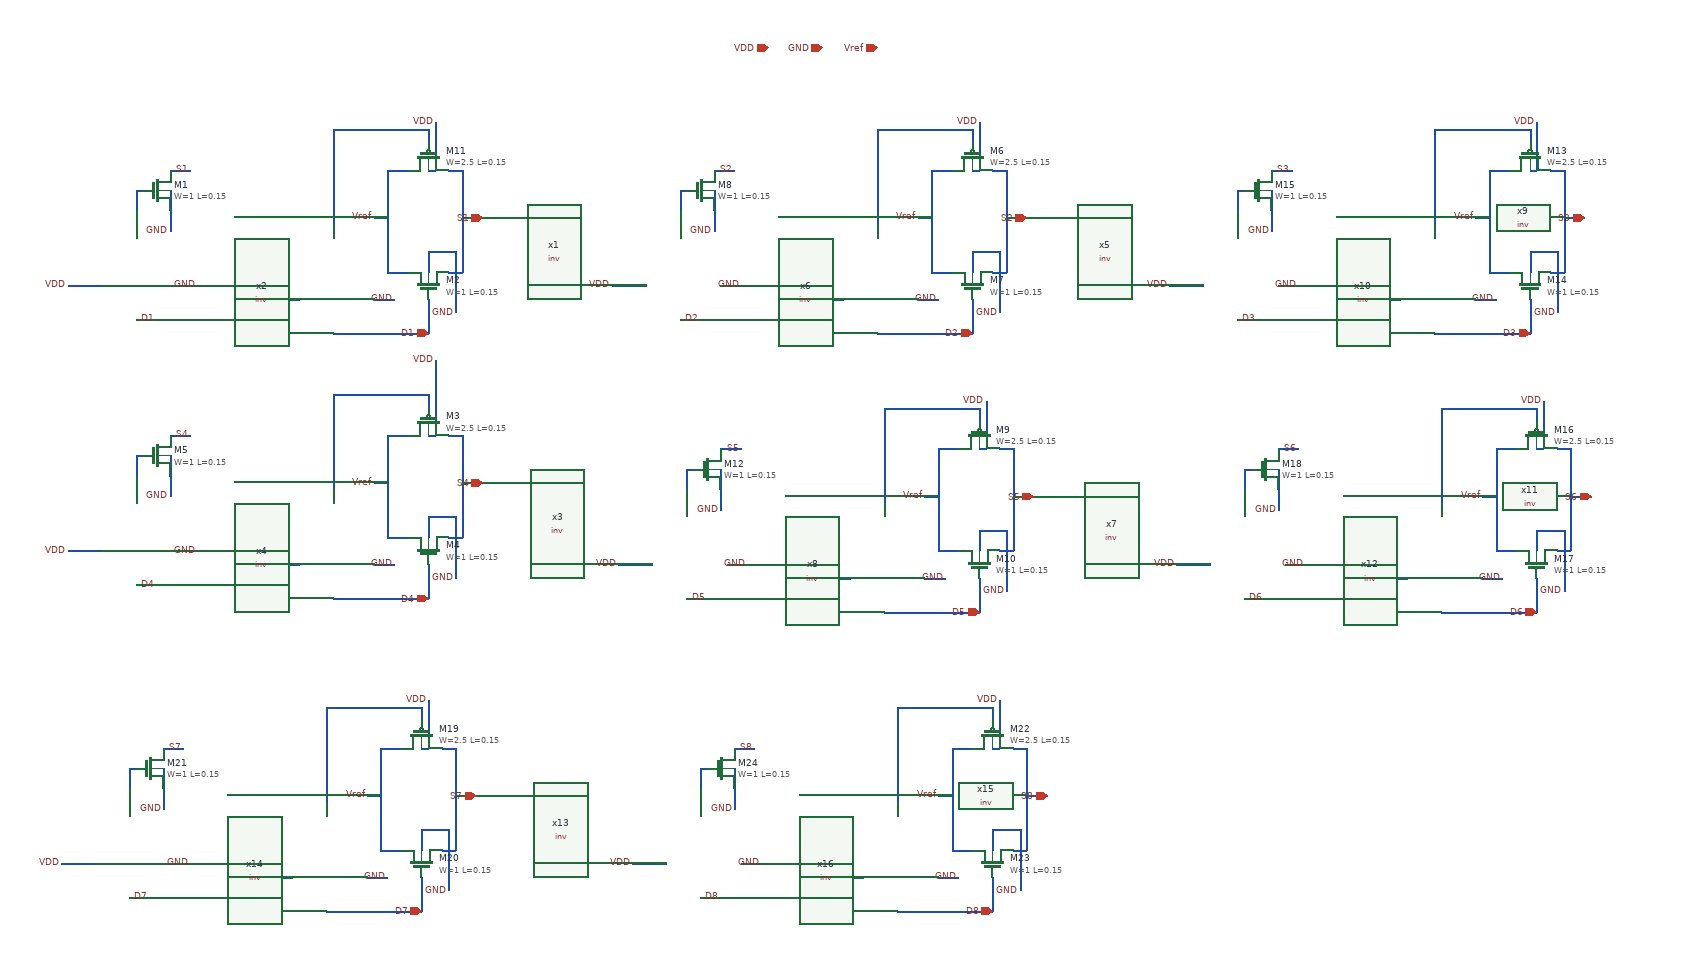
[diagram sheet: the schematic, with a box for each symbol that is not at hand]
v {xschem version=3.4.8RC file_version=1.2}
G {}
K {}
V {}
S {}
E {}
N -90 80 -60 80 {lab=Vref}
N -90 80 -90 230 {lab=Vref}
N -90 230 -60 230 {lab=Vref}
N 0 80 20 80 {lab=S1}
N 20 80 20 230 {lab=S1}
N 0 230 20 230 {lab=S1}
N -30 270 -30 310 {lab=D1}
N -30 200 -30 230 {lab=GND}
N -30 200 10 200 {lab=GND}
N 10 200 10 290 {lab=GND}
N -30 80 -20 80 {lab=VDD}
N -20 10 -20 80 {lab=VDD}
N -170 20 -30 20 {lab=#net1}
N -30 20 -30 40 {lab=#net1}
N -170 320 -50 320 {lab=D1}
N -270 270 -220 270 {lab=VDD}
N -170 20 -170 160 {lab=#net1}
N -110 270 -80 270 {lab=GND}
N -560 250 -510 250 {lab=VDD}
N -400 250 -370 250 {lab=GND}
N -460 110 -460 140 {lab=#net2}
N -460 110 -450 110 {lab=#net2}
N -410 110 -410 140 {lab=GND}
N -460 300 -430 300 {lab=D1}
N -410 80 -380 80 {lab=S1}
N -410 140 -410 170 {lab=GND}
N -30 310 -30 320 {lab=D1}
N -50 320 -30 320 {lab=D1}
N -110 150 -90 150 {lab=Vref}
N 20 150 50 150 {lab=S1}
N -90 470 -60 470 {lab=Vref}
N -90 470 -90 620 {lab=Vref}
N -90 620 -60 620 {lab=Vref}
N 0 470 20 470 {lab=S4}
N 20 470 20 620 {lab=S4}
N 0 620 20 620 {lab=S4}
N -30 660 -30 700 {lab=D4}
N -30 590 -30 620 {lab=GND}
N -30 590 10 590 {lab=GND}
N 10 590 10 680 {lab=GND}
N -170 410 -30 410 {lab=#net3}
N -30 410 -30 430 {lab=#net3}
N -170 710 -50 710 {lab=D4}
N -270 660 -220 660 {lab=VDD}
N -170 410 -170 550 {lab=#net3}
N -110 660 -80 660 {lab=GND}
N -560 640 -510 640 {lab=VDD}
N -400 640 -370 640 {lab=GND}
N -460 500 -460 530 {lab=#net4}
N -460 500 -450 500 {lab=#net4}
N -410 500 -410 530 {lab=GND}
N -460 690 -430 690 {lab=D4}
N -410 470 -380 470 {lab=S4}
N -410 530 -410 560 {lab=GND}
N -30 700 -30 710 {lab=D4}
N -50 710 -30 710 {lab=D4}
N -110 540 -90 540 {lab=Vref}
N 20 540 50 540 {lab=S4}
N 710 80 740 80 {lab=Vref}
N 710 80 710 230 {lab=Vref}
N 710 230 740 230 {lab=Vref}
N 800 80 820 80 {lab=S2}
N 820 80 820 230 {lab=S2}
N 800 230 820 230 {lab=S2}
N 770 270 770 310 {lab=D2}
N 770 200 770 230 {lab=GND}
N 770 200 810 200 {lab=GND}
N 810 200 810 290 {lab=GND}
N 770 80 780 80 {lab=VDD}
N 780 10 780 80 {lab=VDD}
N 630 20 770 20 {lab=#net5}
N 770 20 770 40 {lab=#net5}
N 630 320 750 320 {lab=D2}
N 530 270 580 270 {lab=VDD}
N 630 20 630 160 {lab=#net5}
N 690 270 720 270 {lab=GND}
N 240 250 290 250 {lab=VDD}
N 400 250 430 250 {lab=GND}
N 340 110 340 140 {lab=#net6}
N 340 110 350 110 {lab=#net6}
N 390 110 390 140 {lab=GND}
N 340 300 370 300 {lab=D2}
N 390 80 420 80 {lab=S2}
N 390 140 390 170 {lab=GND}
N 770 310 770 320 {lab=D2}
N 750 320 770 320 {lab=D2}
N 690 150 710 150 {lab=Vref}
N 820 150 850 150 {lab=S2}
N 720 490 750 490 {lab=Vref}
N 720 490 720 640 {lab=Vref}
N 720 640 750 640 {lab=Vref}
N 810 490 830 490 {lab=S5}
N 830 490 830 640 {lab=S5}
N 810 640 830 640 {lab=S5}
N 780 680 780 720 {lab=D5}
N 780 610 780 640 {lab=GND}
N 780 610 820 610 {lab=GND}
N 820 610 820 700 {lab=GND}
N 780 490 790 490 {lab=VDD}
N 790 420 790 490 {lab=VDD}
N 640 430 780 430 {lab=#net7}
N 780 430 780 450 {lab=#net7}
N 640 730 760 730 {lab=D5}
N 540 680 590 680 {lab=VDD}
N 640 430 640 570 {lab=#net7}
N 700 680 730 680 {lab=GND}
N 250 660 300 660 {lab=VDD}
N 410 660 440 660 {lab=GND}
N 350 520 350 550 {lab=#net8}
N 350 520 360 520 {lab=#net8}
N 400 520 400 550 {lab=GND}
N 350 710 380 710 {lab=D5}
N 400 490 430 490 {lab=S5}
N 400 550 400 580 {lab=GND}
N 780 720 780 730 {lab=D5}
N 760 730 780 730 {lab=D5}
N 700 560 720 560 {lab=Vref}
N 830 560 860 560 {lab=S5}
N 1530 80 1560 80 {lab=Vref}
N 1530 80 1530 230 {lab=Vref}
N 1530 230 1560 230 {lab=Vref}
N 1620 80 1640 80 {lab=S3}
N 1640 80 1640 230 {lab=S3}
N 1620 230 1640 230 {lab=S3}
N 1590 270 1590 310 {lab=D3}
N 1590 200 1590 230 {lab=GND}
N 1590 200 1630 200 {lab=GND}
N 1630 200 1630 290 {lab=GND}
N 1590 80 1600 80 {lab=VDD}
N 1600 10 1600 80 {lab=VDD}
N 1450 20 1590 20 {lab=#net9}
N 1590 20 1590 40 {lab=#net9}
N 1450 320 1570 320 {lab=D3}
N 1350 270 1400 270 {lab=VDD}
N 1450 20 1450 160 {lab=#net9}
N 1510 270 1540 270 {lab=GND}
N 1060 250 1110 250 {lab=VDD}
N 1220 250 1250 250 {lab=GND}
N 1160 110 1160 140 {lab=#net10}
N 1160 110 1170 110 {lab=#net10}
N 1210 110 1210 140 {lab=GND}
N 1160 300 1190 300 {lab=D3}
N 1210 80 1240 80 {lab=S3}
N 1210 140 1210 170 {lab=GND}
N 1590 310 1590 320 {lab=D3}
N 1570 320 1590 320 {lab=D3}
N 1510 150 1530 150 {lab=Vref}
N 1640 150 1670 150 {lab=S3}
N 1540 490 1570 490 {lab=Vref}
N 1540 490 1540 640 {lab=Vref}
N 1540 640 1570 640 {lab=Vref}
N 1630 490 1650 490 {lab=S6}
N 1650 490 1650 640 {lab=S6}
N 1630 640 1650 640 {lab=S6}
N 1600 680 1600 720 {lab=D6}
N 1600 610 1600 640 {lab=GND}
N 1600 610 1640 610 {lab=GND}
N 1640 610 1640 700 {lab=GND}
N 1600 490 1610 490 {lab=VDD}
N 1610 420 1610 490 {lab=VDD}
N 1460 430 1600 430 {lab=#net11}
N 1600 430 1600 450 {lab=#net11}
N 1460 730 1580 730 {lab=D6}
N 1360 680 1410 680 {lab=VDD}
N 1460 430 1460 570 {lab=#net11}
N 1520 680 1550 680 {lab=GND}
N 1070 660 1120 660 {lab=VDD}
N 1230 660 1260 660 {lab=GND}
N 1170 520 1170 550 {lab=#net12}
N 1170 520 1180 520 {lab=#net12}
N 1220 520 1220 550 {lab=GND}
N 1170 710 1200 710 {lab=D6}
N 1220 490 1250 490 {lab=S6}
N 1220 550 1220 580 {lab=GND}
N 1600 720 1600 730 {lab=D6}
N 1580 730 1600 730 {lab=D6}
N 1520 560 1540 560 {lab=Vref}
N 1650 560 1680 560 {lab=S6}
N -100 930 -70 930 {lab=Vref}
N -100 930 -100 1080 {lab=Vref}
N -100 1080 -70 1080 {lab=Vref}
N -10 930 10 930 {lab=S7}
N 10 930 10 1080 {lab=S7}
N -10 1080 10 1080 {lab=S7}
N -40 1120 -40 1160 {lab=D7}
N -40 1050 -40 1080 {lab=GND}
N -40 1050 0 1050 {lab=GND}
N 0 1050 0 1140 {lab=GND}
N -40 930 -30 930 {lab=VDD}
N -30 860 -30 930 {lab=VDD}
N -180 870 -40 870 {lab=#net13}
N -40 870 -40 890 {lab=#net13}
N -180 1170 -60 1170 {lab=D7}
N -280 1120 -230 1120 {lab=VDD}
N -180 870 -180 1010 {lab=#net13}
N -120 1120 -90 1120 {lab=GND}
N -570 1100 -520 1100 {lab=VDD}
N -410 1100 -380 1100 {lab=GND}
N -470 960 -470 990 {lab=#net14}
N -470 960 -460 960 {lab=#net14}
N -420 960 -420 990 {lab=GND}
N -470 1150 -440 1150 {lab=D7}
N -420 930 -390 930 {lab=S7}
N -420 990 -420 1020 {lab=GND}
N -40 1160 -40 1170 {lab=D7}
N -60 1170 -40 1170 {lab=D7}
N -120 1000 -100 1000 {lab=Vref}
N 10 1000 40 1000 {lab=S7}
N 740 930 770 930 {lab=Vref}
N 740 930 740 1080 {lab=Vref}
N 740 1080 770 1080 {lab=Vref}
N 830 930 850 930 {lab=S8}
N 850 930 850 1080 {lab=S8}
N 830 1080 850 1080 {lab=S8}
N 800 1120 800 1160 {lab=D8}
N 800 1050 800 1080 {lab=GND}
N 800 1050 840 1050 {lab=GND}
N 840 1050 840 1140 {lab=GND}
N 800 930 810 930 {lab=VDD}
N 810 860 810 930 {lab=VDD}
N 660 870 800 870 {lab=#net15}
N 800 870 800 890 {lab=#net15}
N 660 1170 780 1170 {lab=D8}
N 560 1120 610 1120 {lab=VDD}
N 660 870 660 1010 {lab=#net15}
N 720 1120 750 1120 {lab=GND}
N 270 1100 320 1100 {lab=VDD}
N 430 1100 460 1100 {lab=GND}
N 370 960 370 990 {lab=#net16}
N 370 960 380 960 {lab=#net16}
N 420 960 420 990 {lab=GND}
N 370 1150 400 1150 {lab=D8}
N 420 930 450 930 {lab=S8}
N 420 990 420 1020 {lab=GND}
N 800 1160 800 1170 {lab=D8}
N 780 1170 800 1170 {lab=D8}
N 720 1000 740 1000 {lab=Vref}
N 850 1000 880 1000 {lab=S8}
N -30 470 -20 470 {lab=VDD}
N -20 360 -20 470 {lab=VDD}
C {iopin.sym} 470 -100 0 0 {name=p4 lab=VDD}
C {iopin.sym} 550 -100 0 0 {name=p5 lab=GND}
C {sky130_fd_pr/pfet_01v8.sym} -30 60 3 1 {name=M11
L=0.15
W=2.5
nf=1 mult=1
model=pfet_01v8
spiceprefix=X
}
C {sky130_fd_pr/nfet_01v8.sym} -30 250 1 1 {name=M2
L=0.15
W=1  
nf=1 mult=1
model=nfet_01v8
spiceprefix=X
}
C {sky130_fd_pr/nfet_01v8.sym} -430 110 0 0 {name=M1
L=0.15
W=1  
nf=1 mult=1
model=nfet_01v8
spiceprefix=X
}
C {inv.sym} 60 250 3 0 {name=x1}
C {lab_wire.sym} -270 270 0 0 {name=p6 sig_type=std_logic lab=VDD}
C {lab_wire.sym} -80 270 0 0 {name=p7 sig_type=std_logic lab=GND}
C {inv.sym} -230 230 3 0 {name=x2}
C {lab_wire.sym} -560 250 0 0 {name=p8 sig_type=std_logic lab=VDD}
C {lab_wire.sym} -370 250 0 0 {name=p9 sig_type=std_logic lab=GND}
C {lab_wire.sym} -430 300 0 0 {name=p10 sig_type=std_logic lab=D1}
C {lab_wire.sym} -380 80 0 0 {name=p11 sig_type=std_logic lab=S1}
C {lab_wire.sym} -20 10 0 0 {name=p12 sig_type=std_logic lab=VDD}
C {lab_wire.sym} 10 290 0 0 {name=p13 sig_type=std_logic lab=GND}
C {lab_wire.sym} -410 170 0 0 {name=p14 sig_type=std_logic lab=GND}
C {iopin.sym} -30 320 0 0 {name=p1 lab=D1}
C {iopin.sym} 630 -100 0 0 {name=p2 lab=Vref}
C {lab_wire.sym} -110 150 0 0 {name=p3 sig_type=std_logic lab=Vref}
C {iopin.sym} 50 150 0 0 {name=p15 lab=S1
}
C {sky130_fd_pr/pfet_01v8.sym} -30 450 3 1 {name=M3
L=0.15
W=2.5
nf=1 mult=1
model=pfet_01v8
spiceprefix=X
}
C {sky130_fd_pr/nfet_01v8.sym} -30 640 1 1 {name=M4
L=0.15
W=1  
nf=1 mult=1
model=nfet_01v8
spiceprefix=X
}
C {sky130_fd_pr/nfet_01v8.sym} -430 500 0 0 {name=M5
L=0.15
W=1  
nf=1 mult=1
model=nfet_01v8
spiceprefix=X
}
C {inv.sym} 60 640 3 0 {name=x3}
C {lab_wire.sym} -270 660 0 0 {name=p16 sig_type=std_logic lab=VDD}
C {lab_wire.sym} -80 660 0 0 {name=p17 sig_type=std_logic lab=GND}
C {inv.sym} -230 620 3 0 {name=x4}
C {lab_wire.sym} -560 640 0 0 {name=p18 sig_type=std_logic lab=VDD}
C {lab_wire.sym} -370 640 0 0 {name=p19 sig_type=std_logic lab=GND}
C {lab_wire.sym} -430 690 0 0 {name=p20 sig_type=std_logic lab=D4}
C {lab_wire.sym} -380 470 0 0 {name=p21 sig_type=std_logic lab=S4}
C {lab_wire.sym} 10 680 0 0 {name=p22 sig_type=std_logic lab=GND}
C {lab_wire.sym} -410 560 0 0 {name=p23 sig_type=std_logic lab=GND}
C {iopin.sym} -30 710 0 0 {name=p24 lab=D4}
C {lab_wire.sym} -110 540 0 0 {name=p25 sig_type=std_logic lab=Vref}
C {iopin.sym} 50 540 0 0 {name=p26 lab=S4
}
C {sky130_fd_pr/pfet_01v8.sym} 770 60 3 1 {name=M6
L=0.15
W=2.5
nf=1 mult=1
model=pfet_01v8
spiceprefix=X
}
C {sky130_fd_pr/nfet_01v8.sym} 770 250 1 1 {name=M7
L=0.15
W=1  
nf=1 mult=1
model=nfet_01v8
spiceprefix=X
}
C {sky130_fd_pr/nfet_01v8.sym} 370 110 0 0 {name=M8
L=0.15
W=1  
nf=1 mult=1
model=nfet_01v8
spiceprefix=X
}
C {inv.sym} 860 250 3 0 {name=x5}
C {lab_wire.sym} 530 270 0 0 {name=p27 sig_type=std_logic lab=VDD}
C {lab_wire.sym} 720 270 0 0 {name=p28 sig_type=std_logic lab=GND}
C {inv.sym} 570 230 3 0 {name=x6}
C {lab_wire.sym} 240 250 0 0 {name=p29 sig_type=std_logic lab=VDD}
C {lab_wire.sym} 430 250 0 0 {name=p30 sig_type=std_logic lab=GND}
C {lab_wire.sym} 370 300 0 0 {name=p31 sig_type=std_logic lab=D2}
C {lab_wire.sym} 420 80 0 0 {name=p32 sig_type=std_logic lab=S2}
C {lab_wire.sym} 780 10 0 0 {name=p33 sig_type=std_logic lab=VDD}
C {lab_wire.sym} 810 290 0 0 {name=p34 sig_type=std_logic lab=GND}
C {lab_wire.sym} 390 170 0 0 {name=p35 sig_type=std_logic lab=GND}
C {iopin.sym} 770 320 0 0 {name=p36 lab=D2}
C {lab_wire.sym} 690 150 0 0 {name=p37 sig_type=std_logic lab=Vref}
C {iopin.sym} 850 150 0 0 {name=p38 lab=S2
}
C {sky130_fd_pr/pfet_01v8.sym} 780 470 3 1 {name=M9
L=0.15
W=2.5
nf=1 mult=1
model=pfet_01v8
spiceprefix=X
}
C {sky130_fd_pr/nfet_01v8.sym} 780 660 1 1 {name=M10
L=0.15
W=1  
nf=1 mult=1
model=nfet_01v8
spiceprefix=X
}
C {sky130_fd_pr/nfet_01v8.sym} 380 520 0 0 {name=M12
L=0.15
W=1  
nf=1 mult=1
model=nfet_01v8
spiceprefix=X
}
C {inv.sym} 870 660 3 0 {name=x7}
C {lab_wire.sym} 540 680 0 0 {name=p39 sig_type=std_logic lab=VDD}
C {lab_wire.sym} 730 680 0 0 {name=p40 sig_type=std_logic lab=GND}
C {inv.sym} 580 640 3 0 {name=x8}
C {lab_wire.sym} 250 660 0 0 {name=p41 sig_type=std_logic lab=VDD}
C {lab_wire.sym} 440 660 0 0 {name=p42 sig_type=std_logic lab=GND}
C {lab_wire.sym} 380 710 0 0 {name=p43 sig_type=std_logic lab=D5}
C {lab_wire.sym} 430 490 0 0 {name=p44 sig_type=std_logic lab=S5}
C {lab_wire.sym} 790 420 0 0 {name=p45 sig_type=std_logic lab=VDD}
C {lab_wire.sym} 820 700 0 0 {name=p46 sig_type=std_logic lab=GND}
C {lab_wire.sym} 400 580 0 0 {name=p47 sig_type=std_logic lab=GND}
C {iopin.sym} 780 730 0 0 {name=p48 lab=D5}
C {lab_wire.sym} 700 560 0 0 {name=p49 sig_type=std_logic lab=Vref}
C {iopin.sym} 860 560 0 0 {name=p50 lab=S5
}
C {sky130_fd_pr/pfet_01v8.sym} 1590 60 3 1 {name=M13
L=0.15
W=2.5
nf=1 mult=1
model=pfet_01v8
spiceprefix=X
}
C {sky130_fd_pr/nfet_01v8.sym} 1590 250 1 1 {name=M14
L=0.15
W=1  
nf=1 mult=1
model=nfet_01v8
spiceprefix=X
}
C {sky130_fd_pr/nfet_01v8.sym} 1190 110 0 0 {name=M15
L=0.15
W=1  
nf=1 mult=1
model=nfet_01v8
spiceprefix=X
}
C {inv.sym} 1680 250 3 0 {name=x9}
C {lab_wire.sym} 1350 270 0 0 {name=p51 sig_type=std_logic lab=VDD}
C {lab_wire.sym} 1540 270 0 0 {name=p52 sig_type=std_logic lab=GND}
C {inv.sym} 1390 230 3 0 {name=x10}
C {lab_wire.sym} 1060 250 0 0 {name=p53 sig_type=std_logic lab=VDD}
C {lab_wire.sym} 1250 250 0 0 {name=p54 sig_type=std_logic lab=GND}
C {lab_wire.sym} 1190 300 0 0 {name=p55 sig_type=std_logic lab=D3}
C {lab_wire.sym} 1240 80 0 0 {name=p56 sig_type=std_logic lab=S3}
C {lab_wire.sym} 1600 10 0 0 {name=p57 sig_type=std_logic lab=VDD}
C {lab_wire.sym} 1630 290 0 0 {name=p58 sig_type=std_logic lab=GND}
C {lab_wire.sym} 1210 170 0 0 {name=p59 sig_type=std_logic lab=GND}
C {iopin.sym} 1590 320 0 0 {name=p60 lab=D3}
C {lab_wire.sym} 1510 150 0 0 {name=p61 sig_type=std_logic lab=Vref}
C {iopin.sym} 1670 150 0 0 {name=p62 lab=S3
}
C {sky130_fd_pr/pfet_01v8.sym} 1600 470 3 1 {name=M16
L=0.15
W=2.5
nf=1 mult=1
model=pfet_01v8
spiceprefix=X
}
C {sky130_fd_pr/nfet_01v8.sym} 1600 660 1 1 {name=M17
L=0.15
W=1  
nf=1 mult=1
model=nfet_01v8
spiceprefix=X
}
C {sky130_fd_pr/nfet_01v8.sym} 1200 520 0 0 {name=M18
L=0.15
W=1  
nf=1 mult=1
model=nfet_01v8
spiceprefix=X
}
C {inv.sym} 1690 660 3 0 {name=x11}
C {lab_wire.sym} 1360 680 0 0 {name=p63 sig_type=std_logic lab=VDD}
C {lab_wire.sym} 1550 680 0 0 {name=p64 sig_type=std_logic lab=GND}
C {inv.sym} 1400 640 3 0 {name=x12}
C {lab_wire.sym} 1070 660 0 0 {name=p65 sig_type=std_logic lab=VDD}
C {lab_wire.sym} 1260 660 0 0 {name=p66 sig_type=std_logic lab=GND}
C {lab_wire.sym} 1200 710 0 0 {name=p67 sig_type=std_logic lab=D6}
C {lab_wire.sym} 1250 490 0 0 {name=p68 sig_type=std_logic lab=S6}
C {lab_wire.sym} 1610 420 0 0 {name=p69 sig_type=std_logic lab=VDD}
C {lab_wire.sym} 1640 700 0 0 {name=p70 sig_type=std_logic lab=GND}
C {lab_wire.sym} 1220 580 0 0 {name=p71 sig_type=std_logic lab=GND}
C {iopin.sym} 1600 730 0 0 {name=p72 lab=D6}
C {lab_wire.sym} 1520 560 0 0 {name=p73 sig_type=std_logic lab=Vref}
C {iopin.sym} 1680 560 0 0 {name=p74 lab=S6
}
C {sky130_fd_pr/pfet_01v8.sym} -40 910 3 1 {name=M19
L=0.15
W=2.5
nf=1 mult=1
model=pfet_01v8
spiceprefix=X
}
C {sky130_fd_pr/nfet_01v8.sym} -40 1100 1 1 {name=M20
L=0.15
W=1  
nf=1 mult=1
model=nfet_01v8
spiceprefix=X
}
C {sky130_fd_pr/nfet_01v8.sym} -440 960 0 0 {name=M21
L=0.15
W=1  
nf=1 mult=1
model=nfet_01v8
spiceprefix=X
}
C {inv.sym} 50 1100 3 0 {name=x13}
C {lab_wire.sym} -280 1120 0 0 {name=p75 sig_type=std_logic lab=VDD}
C {lab_wire.sym} -90 1120 0 0 {name=p76 sig_type=std_logic lab=GND}
C {inv.sym} -240 1080 3 0 {name=x14}
C {lab_wire.sym} -570 1100 0 0 {name=p77 sig_type=std_logic lab=VDD}
C {lab_wire.sym} -380 1100 0 0 {name=p78 sig_type=std_logic lab=GND}
C {lab_wire.sym} -440 1150 0 0 {name=p79 sig_type=std_logic lab=D7}
C {lab_wire.sym} -390 930 0 0 {name=p80 sig_type=std_logic lab=S7}
C {lab_wire.sym} -30 860 0 0 {name=p81 sig_type=std_logic lab=VDD}
C {lab_wire.sym} 0 1140 0 0 {name=p82 sig_type=std_logic lab=GND}
C {lab_wire.sym} -420 1020 0 0 {name=p83 sig_type=std_logic lab=GND}
C {iopin.sym} -40 1170 0 0 {name=p84 lab=D7}
C {lab_wire.sym} -120 1000 0 0 {name=p85 sig_type=std_logic lab=Vref}
C {iopin.sym} 40 1000 0 0 {name=p86 lab=S7
}
C {sky130_fd_pr/pfet_01v8.sym} 800 910 3 1 {name=M22
L=0.15
W=2.5
nf=1 mult=1
model=pfet_01v8
spiceprefix=X
}
C {sky130_fd_pr/nfet_01v8.sym} 800 1100 1 1 {name=M23
L=0.15
W=1  
nf=1 mult=1
model=nfet_01v8
spiceprefix=X
}
C {sky130_fd_pr/nfet_01v8.sym} 400 960 0 0 {name=M24
L=0.15
W=1  
nf=1 mult=1
model=nfet_01v8
spiceprefix=X
}
C {inv.sym} 890 1100 3 0 {name=x15}
C {lab_wire.sym} 560 1120 0 0 {name=p87 sig_type=std_logic lab=VDD}
C {lab_wire.sym} 750 1120 0 0 {name=p88 sig_type=std_logic lab=GND}
C {inv.sym} 600 1080 3 0 {name=x16}
C {lab_wire.sym} 270 1100 0 0 {name=p89 sig_type=std_logic lab=VDD}
C {lab_wire.sym} 460 1100 0 0 {name=p90 sig_type=std_logic lab=GND}
C {lab_wire.sym} 400 1150 0 0 {name=p91 sig_type=std_logic lab=D8}
C {lab_wire.sym} 450 930 0 0 {name=p92 sig_type=std_logic lab=S8}
C {lab_wire.sym} 810 860 0 0 {name=p93 sig_type=std_logic lab=VDD}
C {lab_wire.sym} 840 1140 0 0 {name=p94 sig_type=std_logic lab=GND}
C {lab_wire.sym} 420 1020 0 0 {name=p95 sig_type=std_logic lab=GND}
C {iopin.sym} 800 1170 0 0 {name=p96 lab=D8}
C {lab_wire.sym} 720 1000 0 0 {name=p97 sig_type=std_logic lab=Vref}
C {iopin.sym} 880 1000 0 0 {name=p98 lab=S8
}
C {lab_wire.sym} -20 360 0 0 {name=p99 sig_type=std_logic lab=VDD}
